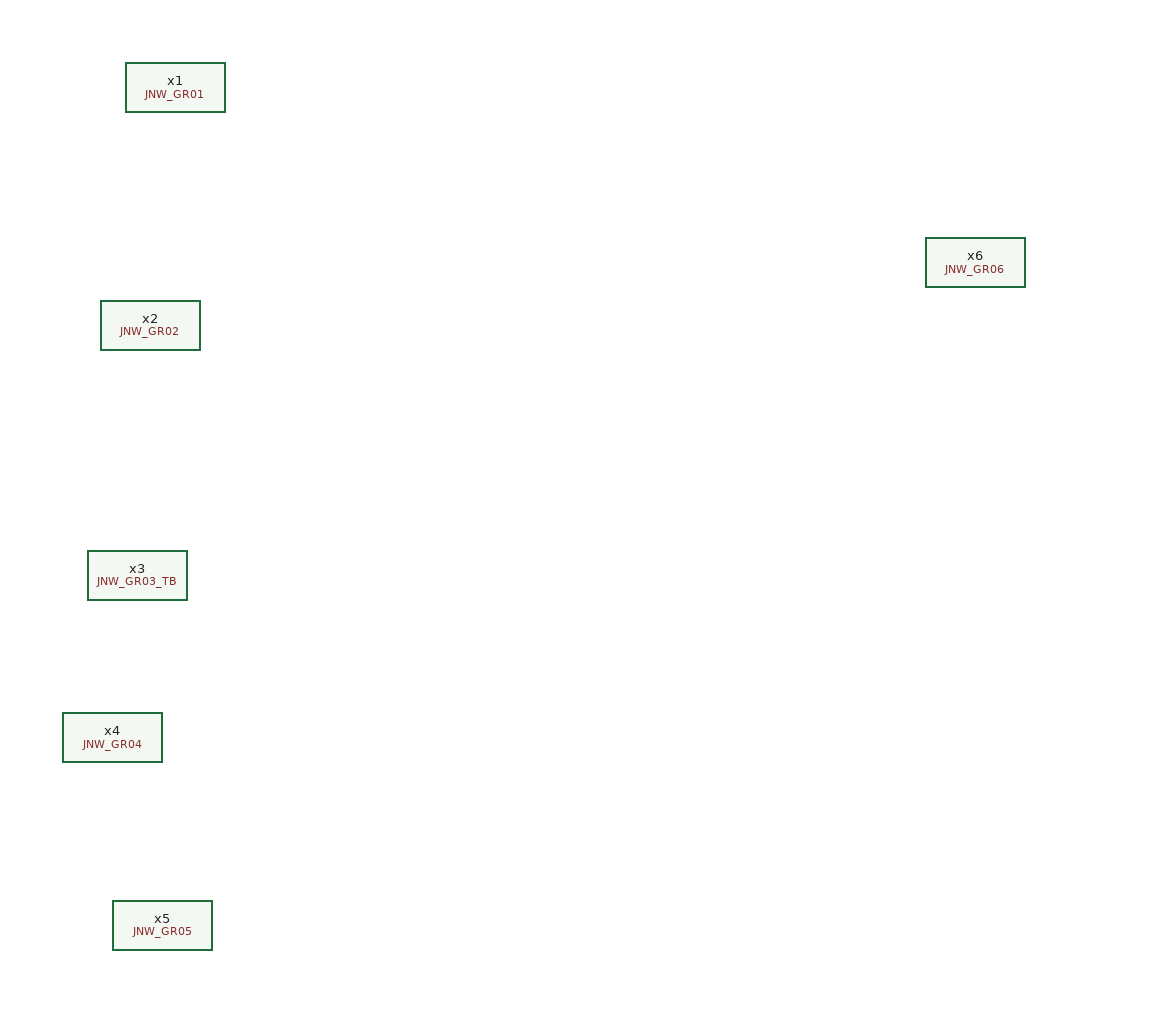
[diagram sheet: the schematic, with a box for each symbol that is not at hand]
v {xschem version=3.4.5 file_version=1.2
}
G {}
K {}
V {}
S {}
E {}
C {JNW_GR01_SKY130A/JNW_GR01.sym} 230 -40 0 0 {name=x1}
C {JNW_GR03_SKY130A/JNW_GR03_TB.sym} 200 350 0 0 {name=x3}
C {JNW_GR04_SKY130A/JNW_GR04.sym} 180 480 0 0 {name=x4}
C {JNW_GR05_SKY130A/JNW_GR05.sym} 220 630 0 0 {name=x5}
C {JNW_GR02_SKY130A/JNW_GR02.sym} 210 150 0 0 {name=x2}
C {JNW_GR06_SKY130A/JNW_GR06.sym} 870 100 0 0 {name=x6}
